VERSION 5.8 ;
DIVIDERCHAR "/" ;
BUSBITCHARS "[]" ;
UNITS
  DATABASE MICRONS 2000 ;
END UNITS

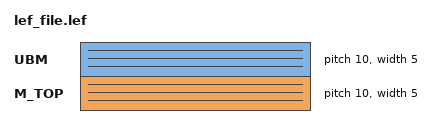
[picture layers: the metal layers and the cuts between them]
LAYER M_TOP
  TYPE ROUTING ;
  DIRECTION HORIZONTAL ;
  PITCH 10.000 ;
  WIDTH 5.000 ;
  SPACING 0.000 ;
  RESISTANCE RPERSQ 0.01 ;
  CAPACITANCE CPERSQDIST 0.001 ;
END M_TOP

LAYER UBM
  TYPE ROUTING ;
  DIRECTION HORIZONTAL ;
  PITCH 10.000 ;
  WIDTH 5.000 ;
  SPACING 0.000 ;
  RESISTANCE RPERSQ 0.01 ;
  CAPACITANCE CPERSQDIST 0.001 ;
END UBM

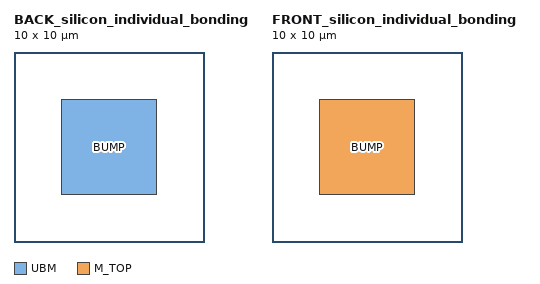
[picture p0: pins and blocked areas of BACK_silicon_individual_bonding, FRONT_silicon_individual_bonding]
MACRO BACK_silicon_individual_bonding
  CLASS COVER BUMP ;
  FOREIGN silicon_individual_bonding 0 0 ;
  ORIGIN 0 0 ;
  SIZE 10.000 BY 10.000 ;
  PIN BUMP
    DIRECTION INOUT ;
    USE SIGNAL ;
    PORT
      LAYER UBM ;
        RECT 2.500 2.500 7.500 7.500 ;
    END
  END BUMP
END BACK_silicon_individual_bonding

MACRO FRONT_silicon_individual_bonding
  CLASS COVER BUMP ;
  FOREIGN silicon_individual_bonding 0 0 ;
  ORIGIN 0 0 ;
  SIZE 10.000 BY 10.000 ;
  PIN BUMP
    DIRECTION INOUT ;
    USE SIGNAL ;
    PORT
      LAYER M_TOP ;
        RECT 2.500 2.500 7.500 7.500 ;
    END
  END BUMP
END FRONT_silicon_individual_bonding

